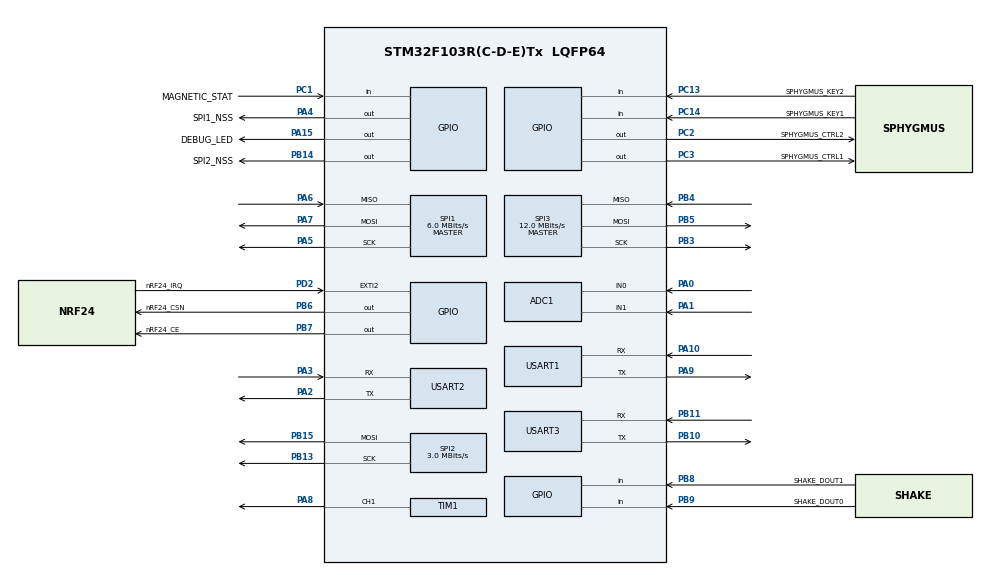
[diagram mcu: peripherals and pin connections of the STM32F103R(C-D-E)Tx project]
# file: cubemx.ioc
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ADC1.Channel-0\#ChannelRegularConversion=ADC_CHANNEL_0
ADC1.Channel-2\#ChannelRegularConversion=ADC_CHANNEL_1
ADC1.ContinuousConvMode=ENABLE
ADC1.NbrOfConversion=2
ADC1.NbrOfConversionFlag=1
ADC1.Rank-0\#ChannelRegularConversion=1
ADC1.Rank-2\#ChannelRegularConversion=2
ADC1.SamplingTime-0\#ChannelRegularConversion=ADC_SAMPLETIME_1CYCLE_5
ADC1.SamplingTime-2\#ChannelRegularConversion=ADC_SAMPLETIME_1CYCLE_5
ADC1.master=1
Dma.Request0=TIM1_CH1
Dma.TIM1_CH1.0.Direction=DMA_MEMORY_TO_PERIPH
Dma.TIM1_CH1.0.Instance=DMA1_Channel2
Dma.TIM1_CH1.0.MemDataAlignment=DMA_MDATAALIGN_HALFWORD
Dma.TIM1_CH1.0.MemInc=DMA_MINC_ENABLE
Dma.TIM1_CH1.0.Mode=DMA_CIRCULAR
Dma.TIM1_CH1.0.PeriphDataAlignment=DMA_PDATAALIGN_HALFWORD
Dma.TIM1_CH1.0.PeriphInc=DMA_PINC_DISABLE
Dma.TIM1_CH1.0.Priority=DMA_PRIORITY_LOW
Mcu.Family=STM32F1
Mcu.Name=STM32F103R(C-D-E)Tx
Mcu.Package=LQFP64
NVIC.DMA1_Channel2_IRQn=true\:0\:0\:false\:false\:true\:false\:true\:true
NVIC.PriorityGroup=NVIC_PRIORITYGROUP_4
PA0-WKUP.Signal=ADCx_IN0
PA1.Signal=ADCx_IN1
PA10.Mode=Asynchronous
PA10.Signal=USART1_RX
PA13.Mode=Serial_Wire
PA13.Signal=SYS_JTMS-SWDIO
PA14.Mode=Serial_Wire
PA14.Signal=SYS_JTCK-SWCLK
PA15.GPIO_Label=DEBUG_LED
PA15.GPIO_PuPd=GPIO_NOPULL
PA15.GPIO_Speed=GPIO_SPEED_FREQ_HIGH
PA15.PinState=GPIO_PIN_RESET
PA15.Signal=GPIO_Output
PA2.Mode=Asynchronous
PA2.Signal=USART2_TX
PA3.Mode=Asynchronous
PA3.Signal=USART2_RX
PA4.GPIO_Label=SPI1_NSS
PA4.Signal=GPIO_Output
PA5.Mode=Full_Duplex_Master
PA5.Signal=SPI1_SCK
PA6.Mode=Full_Duplex_Master
PA6.Signal=SPI1_MISO
PA7.Mode=Full_Duplex_Master
PA7.Signal=SPI1_MOSI
PA8.Signal=S_TIM1_CH1
PA9.Mode=Asynchronous
PA9.Signal=USART1_TX
PB10.Mode=Asynchronous
PB10.Signal=USART3_TX
PB11.Mode=Asynchronous
PB11.Signal=USART3_RX
PB13.Mode=TX_Only_Simplex_Unidirect_Master
PB13.Signal=SPI2_SCK
PB14.GPIO_Label=SPI2_NSS
PB14.GPIO_Speed=GPIO_SPEED_FREQ_LOW
PB14.Signal=GPIO_Output
PB15.Mode=TX_Only_Simplex_Unidirect_Master
PB15.Signal=SPI2_MOSI
PB3.Mode=Full_Duplex_Master
PB3.Signal=SPI3_SCK
PB4.Mode=Full_Duplex_Master
PB4.Signal=SPI3_MISO
PB5.Mode=Full_Duplex_Master
PB5.Signal=SPI3_MOSI
PB6.GPIO_Label=nRF24_CSN
PB6.Signal=GPIO_Output
PB7.GPIO_Label=nRF24_CE
PB7.Signal=GPIO_Output
PB8.GPIO_Label=SHAKE_DOUT1
PB8.Signal=GPIO_Input
PB9.GPIO_Label=SHAKE_DOUT0
PB9.Signal=GPIO_Input
PC1.GPIO_Label=MAGNETIC_STAT
PC1.Signal=GPIO_Input
PC13-TAMPER-RTC.GPIO_Label=SPHYGMUS_KEY2
PC13-TAMPER-RTC.GPIO_PuPd=GPIO_PULLDOWN
PC13-TAMPER-RTC.Signal=GPIO_Input
PC14-OSC32_IN.GPIO_Label=SPHYGMUS_KEY1
PC14-OSC32_IN.GPIO_PuPd=GPIO_PULLDOWN
PC14-OSC32_IN.Signal=GPIO_Input
PC2.GPIO_Label=SPHYGMUS_CTRL2
PC2.GPIO_PuPd=GPIO_PULLUP
PC2.GPIO_Speed=GPIO_SPEED_FREQ_MEDIUM
PC2.Signal=GPIO_Output
PC3.GPIO_Label=SPHYGMUS_CTRL1
PC3.GPIO_PuPd=GPIO_PULLUP
PC3.GPIO_Speed=GPIO_SPEED_FREQ_MEDIUM
PC3.Signal=GPIO_Output
PD0-OSC_IN.Mode=HSE-External-Oscillator
PD0-OSC_IN.Signal=RCC_OSC_IN
PD1-OSC_OUT.Mode=HSE-External-Oscillator
PD1-OSC_OUT.Signal=RCC_OSC_OUT
PD2.GPIO_Label=nRF24_IRQ
PD2.GPIO_PuPd=GPIO_PULLUP
PD2.Signal=GPXTI2
ProjectManager.HeapSize=0x200
ProjectManager.StackSize=0x400
ProjectManager.TargetToolchain=MDK-ARM V5.32
RCC.ADCPresc=RCC_ADCPCLK2_DIV4
RCC.AHBFreq_Value=48000000
RCC.APB1CLKDivider=RCC_HCLK_DIV2
RCC.APB1Freq_Value=24000000
RCC.APB1TimFreq_Value=48000000
RCC.APB2Freq_Value=48000000
RCC.APB2TimFreq_Value=48000000
RCC.HCLKFreq_Value=48000000
RCC.PLLMUL=RCC_PLL_MUL6
RCC.PLLSourceVirtual=RCC_PLLSOURCE_HSE
RCC.SYSCLKFreq_VALUE=48000000
RCC.SYSCLKSource=RCC_SYSCLKSOURCE_PLLCLK
RCC.USBFreq_Value=48000000
SH.ADCx_IN0.0=ADC1_IN0,IN0
SH.ADCx_IN1.0=ADC1_IN1,IN1
SH.S_TIM1_CH1.0=TIM1_CH1,Output Compare1 CH1
SPI1.BaudRatePrescaler=SPI_BAUDRATEPRESCALER_8
SPI1.CalculateBaudRate=6.0 MBits/s
SPI1.DataSize=SPI_DATASIZE_16BIT
SPI1.Direction=SPI_DIRECTION_2LINES
SPI1.Mode=SPI_MODE_MASTER
SPI1.VirtualType=VM_MASTER
SPI2.BaudRatePrescaler=SPI_BAUDRATEPRESCALER_8
SPI2.CalculateBaudRate=3.0 MBits/s
SPI2.Direction=SPI_DIRECTION_2LINES
SPI2.Mode=SPI_MODE_MASTER
SPI2.VirtualType=VM_MASTER
SPI3.CalculateBaudRate=12.0 MBits/s
SPI3.Direction=SPI_DIRECTION_2LINES
SPI3.Mode=SPI_MODE_MASTER
SPI3.VirtualType=VM_MASTER
TIM1.Channel-Output\ Compare1\ CH1=TIM_CHANNEL_1
TIM1.Period=89
TIM1.RepetitionCounter=89
USART1.VirtualMode=VM_ASYNC
USART2.VirtualMode=VM_ASYNC
USART3.VirtualMode=VM_ASYNC
VP_TIM1_VS_ClockSourceINT.Mode=Internal
board=custom

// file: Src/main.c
/* USER CODE BEGIN Header */
/**
  ******************************************************************************
  * @file           : main.c
  * @brief          : Main program body
  ******************************************************************************
  * @attention
  *
  * Copyright (c) 2025 STMicroelectronics.
  * All rights reserved.
  *
  * This software is licensed under terms that can be found in the LICENSE file
  * in the root directory of this software component.
  * If no LICENSE file comes with this software, it is provided AS-IS.
  *
  ******************************************************************************
  */
/* USER CODE END Header */
#include "main.h"

/* USER CODE BEGIN Includes */
#include "bsp_sys.h"
/* USER CODE END Includes */

/* USER CODE BEGIN PTD */
ADC_HandleTypeDef hadc1;

SPI_HandleTypeDef hspi1;
SPI_HandleTypeDef hspi2;
SPI_HandleTypeDef hspi3;

TIM_HandleTypeDef htim1;
DMA_HandleTypeDef hdma_tim1_ch1;

UART_HandleTypeDef huart1;
UART_HandleTypeDef huart2;
UART_HandleTypeDef huart3;
/* USER CODE END PTD */

__WEAK int main(void)
{

  /* MCU Configuration--------------------------------------------------------*/

  /* Reset of all peripherals, Initializes the Flash interface and the Systick. */
  HAL_Init();

  /* Configure the system clock */
  SystemClock_Config();

  /* Initialize all configured peripherals */
  MX_GPIO_Init();
  MX_DMA_Init();
  MX_USART1_UART_Init();
  MX_SPI3_Init();
  MX_SPI1_Init();
  MX_ADC1_Init();
  MX_USART3_UART_Init();
  MX_USART2_UART_Init();
  MX_TIM1_Init();
  MX_SPI2_Init();

  /* Infinite loop */
  while (1)
  {

  }
}

void SystemClock_Config(void)
{
  RCC_OscInitTypeDef RCC_OscInitStruct = {0};
  RCC_ClkInitTypeDef RCC_ClkInitStruct = {0};
  RCC_PeriphCLKInitTypeDef PeriphClkInit = {0};

  /** Initializes the RCC Oscillators according to the specified parameters
  * in the RCC_OscInitTypeDef structure.
  */
  RCC_OscInitStruct.OscillatorType = RCC_OSCILLATORTYPE_HSE;
  RCC_OscInitStruct.HSEState = RCC_HSE_ON;
  RCC_OscInitStruct.HSEPredivValue = RCC_HSE_PREDIV_DIV1;
  RCC_OscInitStruct.HSIState = RCC_HSI_ON;
  RCC_OscInitStruct.PLL.PLLState = RCC_PLL_ON;
  RCC_OscInitStruct.PLL.PLLSource = RCC_PLLSOURCE_HSE;
  RCC_OscInitStruct.PLL.PLLMUL = RCC_PLL_MUL9;
  if (HAL_RCC_OscConfig(&RCC_OscInitStruct) != HAL_OK)
  {
    Error_Handler();
  }

  /** Initializes the CPU, AHB and APB buses clocks
  */
  RCC_ClkInitStruct.ClockType = RCC_CLOCKTYPE_HCLK|RCC_CLOCKTYPE_SYSCLK
                              |RCC_CLOCKTYPE_PCLK1|RCC_CLOCKTYPE_PCLK2;
  RCC_ClkInitStruct.SYSCLKSource = RCC_SYSCLKSOURCE_PLLCLK;
  RCC_ClkInitStruct.AHBCLKDivider = RCC_SYSCLK_DIV1;
  RCC_ClkInitStruct.APB1CLKDivider = RCC_HCLK_DIV2;
  RCC_ClkInitStruct.APB2CLKDivider = RCC_HCLK_DIV1;

  if (HAL_RCC_ClockConfig(&RCC_ClkInitStruct, FLASH_LATENCY_2) != HAL_OK)
  {
    Error_Handler();
  }
  PeriphClkInit.PeriphClockSelection = RCC_PERIPHCLK_ADC;
  PeriphClkInit.AdcClockSelection = RCC_ADCPCLK2_DIV6;
  if (HAL_RCCEx_PeriphCLKConfig(&PeriphClkInit) != HAL_OK)
  {
    Error_Handler();
  }
}

void MX_ADC1_Init(void)
{

  ADC_ChannelConfTypeDef sConfig = {0};

  /** Common config
  */
  hadc1.Instance = ADC1;
  hadc1.Init.ScanConvMode = ADC_SCAN_ENABLE;
  hadc1.Init.ContinuousConvMode = ENABLE;
  hadc1.Init.DiscontinuousConvMode = DISABLE;
  hadc1.Init.ExternalTrigConv = ADC_SOFTWARE_START;
  hadc1.Init.DataAlign = ADC_DATAALIGN_RIGHT;
  hadc1.Init.NbrOfConversion = 2;
  if (HAL_ADC_Init(&hadc1) != HAL_OK)
  {
    Error_Handler();
  }

  /** Configure Regular Channel
  */
  sConfig.Channel = ADC_CHANNEL_0;
  sConfig.Rank = ADC_REGULAR_RANK_1;
  sConfig.SamplingTime = ADC_SAMPLETIME_1CYCLE_5;
  if (HAL_ADC_ConfigChannel(&hadc1, &sConfig) != HAL_OK)
  {
    Error_Handler();
  }

  /** Configure Regular Channel
  */
  sConfig.Channel = ADC_CHANNEL_1;
  sConfig.Rank = ADC_REGULAR_RANK_2;
  if (HAL_ADC_ConfigChannel(&hadc1, &sConfig) != HAL_OK)
  {
    Error_Handler();
  }

}

void MX_SPI1_Init(void)
{

  /* SPI1 parameter configuration*/
  hspi1.Instance = SPI1;
  hspi1.Init.Mode = SPI_MODE_MASTER;
  hspi1.Init.Direction = SPI_DIRECTION_2LINES;
  hspi1.Init.DataSize = SPI_DATASIZE_16BIT;
  hspi1.Init.CLKPolarity = SPI_POLARITY_LOW;
  hspi1.Init.CLKPhase = SPI_PHASE_1EDGE;
  hspi1.Init.NSS = SPI_NSS_SOFT;
  hspi1.Init.BaudRatePrescaler = SPI_BAUDRATEPRESCALER_8;
  hspi1.Init.FirstBit = SPI_FIRSTBIT_MSB;
  hspi1.Init.TIMode = SPI_TIMODE_DISABLE;
  hspi1.Init.CRCCalculation = SPI_CRCCALCULATION_DISABLE;
  hspi1.Init.CRCPolynomial = 10;
  if (HAL_SPI_Init(&hspi1) != HAL_OK)
  {
    Error_Handler();
  }

}

void MX_SPI2_Init(void)
{

  /* SPI2 parameter configuration*/
  hspi2.Instance = SPI2;
  hspi2.Init.Mode = SPI_MODE_MASTER;
  hspi2.Init.Direction = SPI_DIRECTION_2LINES;
  hspi2.Init.DataSize = SPI_DATASIZE_8BIT;
  hspi2.Init.CLKPolarity = SPI_POLARITY_LOW;
  hspi2.Init.CLKPhase = SPI_PHASE_1EDGE;
  hspi2.Init.NSS = SPI_NSS_SOFT;
  hspi2.Init.BaudRatePrescaler = SPI_BAUDRATEPRESCALER_8;
  hspi2.Init.FirstBit = SPI_FIRSTBIT_MSB;
  hspi2.Init.TIMode = SPI_TIMODE_DISABLE;
  hspi2.Init.CRCCalculation = SPI_CRCCALCULATION_DISABLE;
  hspi2.Init.CRCPolynomial = 10;
  if (HAL_SPI_Init(&hspi2) != HAL_OK)
  {
    Error_Handler();
  }

}

void MX_SPI3_Init(void)
{

  /* SPI3 parameter configuration*/
  hspi3.Instance = SPI3;
  hspi3.Init.Mode = SPI_MODE_MASTER;
  hspi3.Init.Direction = SPI_DIRECTION_2LINES;
  hspi3.Init.DataSize = SPI_DATASIZE_8BIT;
  hspi3.Init.CLKPolarity = SPI_POLARITY_LOW;
  hspi3.Init.CLKPhase = SPI_PHASE_1EDGE;
  hspi3.Init.NSS = SPI_NSS_SOFT;
  hspi3.Init.BaudRatePrescaler = SPI_BAUDRATEPRESCALER_2;
  hspi3.Init.FirstBit = SPI_FIRSTBIT_MSB;
  hspi3.Init.TIMode = SPI_TIMODE_DISABLE;
  hspi3.Init.CRCCalculation = SPI_CRCCALCULATION_DISABLE;
  hspi3.Init.CRCPolynomial = 10;
  if (HAL_SPI_Init(&hspi3) != HAL_OK)
  {
    Error_Handler();
  }

}

void MX_TIM1_Init(void)
{

  TIM_ClockConfigTypeDef sClockSourceConfig = {0};
  TIM_MasterConfigTypeDef sMasterConfig = {0};
  TIM_OC_InitTypeDef sConfigOC = {0};
  TIM_BreakDeadTimeConfigTypeDef sBreakDeadTimeConfig = {0};

  htim1.Instance = TIM1;
  htim1.Init.Prescaler = 0;
  htim1.Init.CounterMode = TIM_COUNTERMODE_UP;
  htim1.Init.Period = 89;
  htim1.Init.ClockDivision = TIM_CLOCKDIVISION_DIV1;
  htim1.Init.RepetitionCounter = 89;
  htim1.Init.AutoReloadPreload = TIM_AUTORELOAD_PRELOAD_ENABLE;
  if (HAL_TIM_Base_Init(&htim1) != HAL_OK)
  {
    Error_Handler();
  }
  sClockSourceConfig.ClockSource = TIM_CLOCKSOURCE_INTERNAL;
  if (HAL_TIM_ConfigClockSource(&htim1, &sClockSourceConfig) != HAL_OK)
  {
    Error_Handler();
  }
  if (HAL_TIM_PWM_Init(&htim1) != HAL_OK)
  {
    Error_Handler();
  }
  sMasterConfig.MasterOutputTrigger = TIM_TRGO_RESET;
  sMasterConfig.MasterSlaveMode = TIM_MASTERSLAVEMODE_DISABLE;
  if (HAL_TIMEx_MasterConfigSynchronization(&htim1, &sMasterConfig) != HAL_OK)
  {
    Error_Handler();
  }
  sConfigOC.OCMode = TIM_OCMODE_PWM1;
  sConfigOC.Pulse = 0;
  sConfigOC.OCPolarity = TIM_OCPOLARITY_HIGH;
  sConfigOC.OCNPolarity = TIM_OCNPOLARITY_HIGH;
  sConfigOC.OCFastMode = TIM_OCFAST_DISABLE;
  sConfigOC.OCIdleState = TIM_OCIDLESTATE_RESET;
  sConfigOC.OCNIdleState = TIM_OCNIDLESTATE_RESET;
  if (HAL_TIM_PWM_ConfigChannel(&htim1, &sConfigOC, TIM_CHANNEL_1) != HAL_OK)
  {
    Error_Handler();
  }
  sBreakDeadTimeConfig.OffStateRunMode = TIM_OSSR_DISABLE;
  sBreakDeadTimeConfig.OffStateIDLEMode = TIM_OSSI_DISABLE;
  sBreakDeadTimeConfig.LockLevel = TIM_LOCKLEVEL_OFF;
  sBreakDeadTimeConfig.DeadTime = 0;
  sBreakDeadTimeConfig.BreakState = TIM_BREAK_DISABLE;
  sBreakDeadTimeConfig.BreakPolarity = TIM_BREAKPOLARITY_HIGH;
  sBreakDeadTimeConfig.AutomaticOutput = TIM_AUTOMATICOUTPUT_DISABLE;
  if (HAL_TIMEx_ConfigBreakDeadTime(&htim1, &sBreakDeadTimeConfig) != HAL_OK)
  {
    Error_Handler();
  }
  HAL_TIM_MspPostInit(&htim1);

}

void MX_USART1_UART_Init(void)
{

  huart1.Instance = USART1;
  huart1.Init.BaudRate = 115200;
  huart1.Init.WordLength = UART_WORDLENGTH_8B;
  huart1.Init.StopBits = UART_STOPBITS_1;
  huart1.Init.Parity = UART_PARITY_NONE;
  huart1.Init.Mode = UART_MODE_TX_RX;
  huart1.Init.HwFlowCtl = UART_HWCONTROL_NONE;
  huart1.Init.OverSampling = UART_OVERSAMPLING_16;
  if (HAL_UART_Init(&huart1) != HAL_OK)
  {
    Error_Handler();
  }

}

void MX_USART2_UART_Init(void)
{

  huart2.Instance = USART2;
  huart2.Init.BaudRate = 115200;
  huart2.Init.WordLength = UART_WORDLENGTH_8B;
  huart2.Init.StopBits = UART_STOPBITS_1;
  huart2.Init.Parity = UART_PARITY_NONE;
  huart2.Init.Mode = UART_MODE_TX_RX;
  huart2.Init.HwFlowCtl = UART_HWCONTROL_NONE;
  huart2.Init.OverSampling = UART_OVERSAMPLING_16;
  if (HAL_UART_Init(&huart2) != HAL_OK)
  {
    Error_Handler();
  }

}

void MX_USART3_UART_Init(void)
{

  huart3.Instance = USART3;
  huart3.Init.BaudRate = 115200;
  huart3.Init.WordLength = UART_WORDLENGTH_8B;
  huart3.Init.StopBits = UART_STOPBITS_1;
  huart3.Init.Parity = UART_PARITY_NONE;
  huart3.Init.Mode = UART_MODE_TX_RX;
  huart3.Init.HwFlowCtl = UART_HWCONTROL_NONE;
  huart3.Init.OverSampling = UART_OVERSAMPLING_16;
  if (HAL_UART_Init(&huart3) != HAL_OK)
  {
    Error_Handler();
  }

}

void MX_DMA_Init(void)
{

  /* DMA controller clock enable */
  __HAL_RCC_DMA1_CLK_ENABLE();

  /* DMA interrupt init */
  /* DMA1_Channel2_IRQn interrupt configuration */
  HAL_NVIC_SetPriority(DMA1_Channel2_IRQn, 0, 0);
  HAL_NVIC_EnableIRQ(DMA1_Channel2_IRQn);

}

void MX_GPIO_Init(void)
{
  GPIO_InitTypeDef GPIO_InitStruct = {0};

  /* GPIO Ports Clock Enable */
  __HAL_RCC_GPIOC_CLK_ENABLE();
  __HAL_RCC_GPIOD_CLK_ENABLE();
  __HAL_RCC_GPIOA_CLK_ENABLE();
  __HAL_RCC_GPIOB_CLK_ENABLE();

  /*Configure GPIO pin Output Level */
  HAL_GPIO_WritePin(GPIOC, SPHYGMUS_CTRL2_Pin|SPHYGMUS_CTRL1_Pin, GPIO_PIN_RESET);

  /*Configure GPIO pin Output Level */
  HAL_GPIO_WritePin(GPIOA, SPI1_NSS_Pin|DEBUG_LED_Pin, GPIO_PIN_RESET);

  /*Configure GPIO pin Output Level */
  HAL_GPIO_WritePin(GPIOB, SPI2_NSS_Pin|nRF24_CSN_Pin|nRF24_CE_Pin, GPIO_PIN_RESET);

  /*Configure GPIO pins : SPHYGMUS_KEY2_Pin SPHYGMUS_KEY1_Pin */
  GPIO_InitStruct.Pin = SPHYGMUS_KEY2_Pin|SPHYGMUS_KEY1_Pin;
  GPIO_InitStruct.Mode = GPIO_MODE_INPUT;
  GPIO_InitStruct.Pull = GPIO_PULLDOWN;
  HAL_GPIO_Init(GPIOC, &GPIO_InitStruct);

  /*Configure GPIO pin : MAGNETIC_STAT_Pin */
  GPIO_InitStruct.Pin = MAGNETIC_STAT_Pin;
  GPIO_InitStruct.Mode = GPIO_MODE_INPUT;
  GPIO_InitStruct.Pull = GPIO_NOPULL;
  HAL_GPIO_Init(MAGNETIC_STAT_GPIO_Port, &GPIO_InitStruct);

  /*Configure GPIO pins : SPHYGMUS_CTRL2_Pin SPHYGMUS_CTRL1_Pin */
  GPIO_InitStruct.Pin = SPHYGMUS_CTRL2_Pin|SPHYGMUS_CTRL1_Pin;
  GPIO_InitStruct.Mode = GPIO_MODE_OUTPUT_PP;
  GPIO_InitStruct.Pull = GPIO_PULLUP;
  GPIO_InitStruct.Speed = GPIO_SPEED_FREQ_MEDIUM;
  HAL_GPIO_Init(GPIOC, &GPIO_InitStruct);

  /*Configure GPIO pin : SPI1_NSS_Pin */
  GPIO_InitStruct.Pin = SPI1_NSS_Pin;
  GPIO_InitStruct.Mode = GPIO_MODE_OUTPUT_PP;
  GPIO_InitStruct.Pull = GPIO_NOPULL;
  GPIO_InitStruct.Speed = GPIO_SPEED_FREQ_LOW;
  HAL_GPIO_Init(SPI1_NSS_GPIO_Port, &GPIO_InitStruct);

  /*Configure GPIO pins : SPI2_NSS_Pin nRF24_CSN_Pin nRF24_CE_Pin */
  GPIO_InitStruct.Pin = SPI2_NSS_Pin|nRF24_CSN_Pin|nRF24_CE_Pin;
  GPIO_InitStruct.Mode = GPIO_MODE_OUTPUT_PP;
  GPIO_InitStruct.Pull = GPIO_NOPULL;
  GPIO_InitStruct.Speed = GPIO_SPEED_FREQ_LOW;
  HAL_GPIO_Init(GPIOB, &GPIO_InitStruct);

  /*Configure GPIO pin : DEBUG_LED_Pin */
  GPIO_InitStruct.Pin = DEBUG_LED_Pin;
  GPIO_InitStruct.Mode = GPIO_MODE_OUTPUT_PP;
  GPIO_InitStruct.Pull = GPIO_NOPULL;
  GPIO_InitStruct.Speed = GPIO_SPEED_FREQ_HIGH;
  HAL_GPIO_Init(DEBUG_LED_GPIO_Port, &GPIO_InitStruct);

  /*Configure GPIO pin : nRF24_IRQ_Pin */
  GPIO_InitStruct.Pin = nRF24_IRQ_Pin;
  GPIO_InitStruct.Mode = GPIO_MODE_IT_RISING;
  GPIO_InitStruct.Pull = GPIO_PULLUP;
  HAL_GPIO_Init(nRF24_IRQ_GPIO_Port, &GPIO_InitStruct);

  /*Configure GPIO pins : SHAKE_DOUT1_Pin SHAKE_DOUT0_Pin */
  GPIO_InitStruct.Pin = SHAKE_DOUT1_Pin|SHAKE_DOUT0_Pin;
  GPIO_InitStruct.Mode = GPIO_MODE_INPUT;
  GPIO_InitStruct.Pull = GPIO_NOPULL;
  HAL_GPIO_Init(GPIOB, &GPIO_InitStruct);

}
